One B-rep face of a CAD part: STEP entity #55794.
In plain terms, the planar face has unit normal (0, 0, 1).
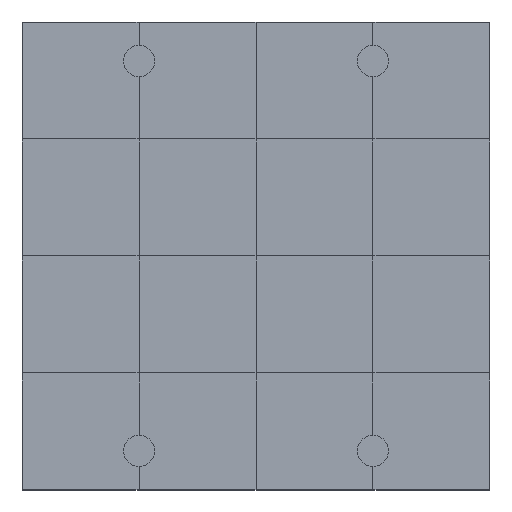
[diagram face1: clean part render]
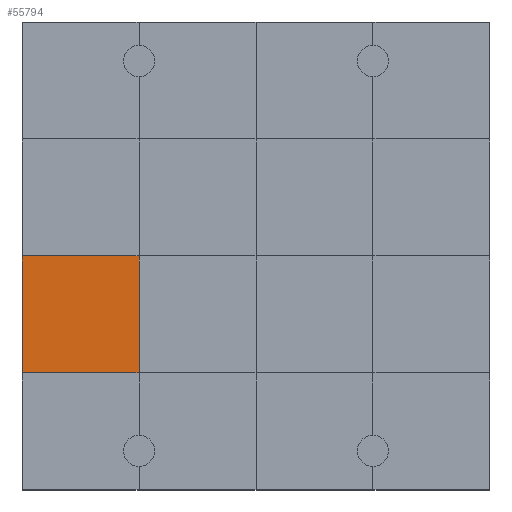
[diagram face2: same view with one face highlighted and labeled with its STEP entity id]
Its self-contained STEP definition (entity closure, numbers rounded to 3 decimals):
#55344 = VERTEX_POINT('',#55345);
#55345 = CARTESIAN_POINT('',(0.,3.,1.2));
#55359 = PLANE('',#55360);
#55360 = AXIS2_PLACEMENT_3D('',#55361,#55362,#55363);
#55361 = CARTESIAN_POINT('',(0.,3.,0.));
#55362 = DIRECTION('',(1.,0.,-0.));
#55363 = DIRECTION('',(0.,0.,1.));
#55385 = PLANE('',#55386);
#55386 = AXIS2_PLACEMENT_3D('',#55387,#55388,#55389);
#55387 = CARTESIAN_POINT('',(0.,0.,1.2));
#55388 = DIRECTION('',(0.,0.,1.));
#55389 = DIRECTION('',(1.,0.,-0.));
#55536 = VERTEX_POINT('',#55537);
#55537 = CARTESIAN_POINT('',(3.,3.,1.2));
#55558 = EDGE_CURVE('',#55344,#55536,#55559,.T.);
#55559 = SURFACE_CURVE('',#55560,(#55564,#55571),.PCURVE_S1.);
#55560 = LINE('',#55561,#55562);
#55561 = CARTESIAN_POINT('',(0.,3.,1.2));
#55562 = VECTOR('',#55563,1.);
#55563 = DIRECTION('',(1.,0.,-0.));
#55564 = PCURVE('',#55385,#55565);
#55565 = DEFINITIONAL_REPRESENTATION('',(#55566),#55570);
#55566 = LINE('',#55567,#55568);
#55567 = CARTESIAN_POINT('',(0.,3.));
#55568 = VECTOR('',#55569,1.);
#55569 = DIRECTION('',(1.,0.));
#55570 = ( GEOMETRIC_REPRESENTATION_CONTEXT(2) 
PARAMETRIC_REPRESENTATION_CONTEXT() REPRESENTATION_CONTEXT('2D SPACE',''
  ) );
#55571 = PCURVE('',#55572,#55577);
#55572 = PLANE('',#55573);
#55573 = AXIS2_PLACEMENT_3D('',#55574,#55575,#55576);
#55574 = CARTESIAN_POINT('',(0.,3.,1.2));
#55575 = DIRECTION('',(0.,0.,1.));
#55576 = DIRECTION('',(1.,0.,-0.));
#55577 = DEFINITIONAL_REPRESENTATION('',(#55578),#55582);
#55578 = LINE('',#55579,#55580);
#55579 = CARTESIAN_POINT('',(0.,0.));
#55580 = VECTOR('',#55581,1.);
#55581 = DIRECTION('',(1.,0.));
#55582 = ( GEOMETRIC_REPRESENTATION_CONTEXT(2) 
PARAMETRIC_REPRESENTATION_CONTEXT() REPRESENTATION_CONTEXT('2D SPACE',''
  ) );
#55617 = VERTEX_POINT('',#55618);
#55618 = CARTESIAN_POINT('',(0.,6.,1.2));
#55644 = EDGE_CURVE('',#55344,#55617,#55645,.T.);
#55645 = SURFACE_CURVE('',#55646,(#55650,#55657),.PCURVE_S1.);
#55646 = LINE('',#55647,#55648);
#55647 = CARTESIAN_POINT('',(0.,3.,1.2));
#55648 = VECTOR('',#55649,1.);
#55649 = DIRECTION('',(-0.,1.,0.));
#55650 = PCURVE('',#55359,#55651);
#55651 = DEFINITIONAL_REPRESENTATION('',(#55652),#55656);
#55652 = LINE('',#55653,#55654);
#55653 = CARTESIAN_POINT('',(1.2,0.));
#55654 = VECTOR('',#55655,1.);
#55655 = DIRECTION('',(0.,-1.));
#55656 = ( GEOMETRIC_REPRESENTATION_CONTEXT(2) 
PARAMETRIC_REPRESENTATION_CONTEXT() REPRESENTATION_CONTEXT('2D SPACE',''
  ) );
#55657 = PCURVE('',#55572,#55658);
#55658 = DEFINITIONAL_REPRESENTATION('',(#55659),#55663);
#55659 = LINE('',#55660,#55661);
#55660 = CARTESIAN_POINT('',(0.,0.));
#55661 = VECTOR('',#55662,1.);
#55662 = DIRECTION('',(0.,1.));
#55663 = ( GEOMETRIC_REPRESENTATION_CONTEXT(2) 
PARAMETRIC_REPRESENTATION_CONTEXT() REPRESENTATION_CONTEXT('2D SPACE',''
  ) );
#55794 = ADVANCED_FACE('',(#55795),#55572,.T.);
#55795 = FACE_BOUND('',#55796,.T.);
#55796 = EDGE_LOOP('',(#55797,#55798,#55799,#55827));
#55797 = ORIENTED_EDGE('',*,*,#55644,.F.);
#55798 = ORIENTED_EDGE('',*,*,#55558,.T.);
#55799 = ORIENTED_EDGE('',*,*,#55800,.T.);
#55800 = EDGE_CURVE('',#55536,#55801,#55803,.T.);
#55801 = VERTEX_POINT('',#55802);
#55802 = CARTESIAN_POINT('',(3.,6.,1.2));
#55803 = SURFACE_CURVE('',#55804,(#55808,#55815),.PCURVE_S1.);
#55804 = LINE('',#55805,#55806);
#55805 = CARTESIAN_POINT('',(3.,3.,1.2));
#55806 = VECTOR('',#55807,1.);
#55807 = DIRECTION('',(-0.,1.,0.));
#55808 = PCURVE('',#55572,#55809);
#55809 = DEFINITIONAL_REPRESENTATION('',(#55810),#55814);
#55810 = LINE('',#55811,#55812);
#55811 = CARTESIAN_POINT('',(3.,0.));
#55812 = VECTOR('',#55813,1.);
#55813 = DIRECTION('',(0.,1.));
#55814 = ( GEOMETRIC_REPRESENTATION_CONTEXT(2) 
PARAMETRIC_REPRESENTATION_CONTEXT() REPRESENTATION_CONTEXT('2D SPACE',''
  ) );
#55815 = PCURVE('',#55816,#55821);
#55816 = PLANE('',#55817);
#55817 = AXIS2_PLACEMENT_3D('',#55818,#55819,#55820);
#55818 = CARTESIAN_POINT('',(3.,3.,1.2));
#55819 = DIRECTION('',(0.,0.,1.));
#55820 = DIRECTION('',(1.,0.,-0.));
#55821 = DEFINITIONAL_REPRESENTATION('',(#55822),#55826);
#55822 = LINE('',#55823,#55824);
#55823 = CARTESIAN_POINT('',(0.,0.));
#55824 = VECTOR('',#55825,1.);
#55825 = DIRECTION('',(0.,1.));
#55826 = ( GEOMETRIC_REPRESENTATION_CONTEXT(2) 
PARAMETRIC_REPRESENTATION_CONTEXT() REPRESENTATION_CONTEXT('2D SPACE',''
  ) );
#55827 = ORIENTED_EDGE('',*,*,#55828,.F.);
#55828 = EDGE_CURVE('',#55617,#55801,#55829,.T.);
#55829 = SURFACE_CURVE('',#55830,(#55834,#55841),.PCURVE_S1.);
#55830 = LINE('',#55831,#55832);
#55831 = CARTESIAN_POINT('',(0.,6.,1.2));
#55832 = VECTOR('',#55833,1.);
#55833 = DIRECTION('',(1.,0.,-0.));
#55834 = PCURVE('',#55572,#55835);
#55835 = DEFINITIONAL_REPRESENTATION('',(#55836),#55840);
#55836 = LINE('',#55837,#55838);
#55837 = CARTESIAN_POINT('',(0.,3.));
#55838 = VECTOR('',#55839,1.);
#55839 = DIRECTION('',(1.,0.));
#55840 = ( GEOMETRIC_REPRESENTATION_CONTEXT(2) 
PARAMETRIC_REPRESENTATION_CONTEXT() REPRESENTATION_CONTEXT('2D SPACE',''
  ) );
#55841 = PCURVE('',#55842,#55847);
#55842 = PLANE('',#55843);
#55843 = AXIS2_PLACEMENT_3D('',#55844,#55845,#55846);
#55844 = CARTESIAN_POINT('',(0.,6.,1.2));
#55845 = DIRECTION('',(0.,0.,1.));
#55846 = DIRECTION('',(1.,0.,-0.));
#55847 = DEFINITIONAL_REPRESENTATION('',(#55848),#55852);
#55848 = LINE('',#55849,#55850);
#55849 = CARTESIAN_POINT('',(0.,0.));
#55850 = VECTOR('',#55851,1.);
#55851 = DIRECTION('',(1.,0.));
#55852 = ( GEOMETRIC_REPRESENTATION_CONTEXT(2) 
PARAMETRIC_REPRESENTATION_CONTEXT() REPRESENTATION_CONTEXT('2D SPACE',''
  ) );
